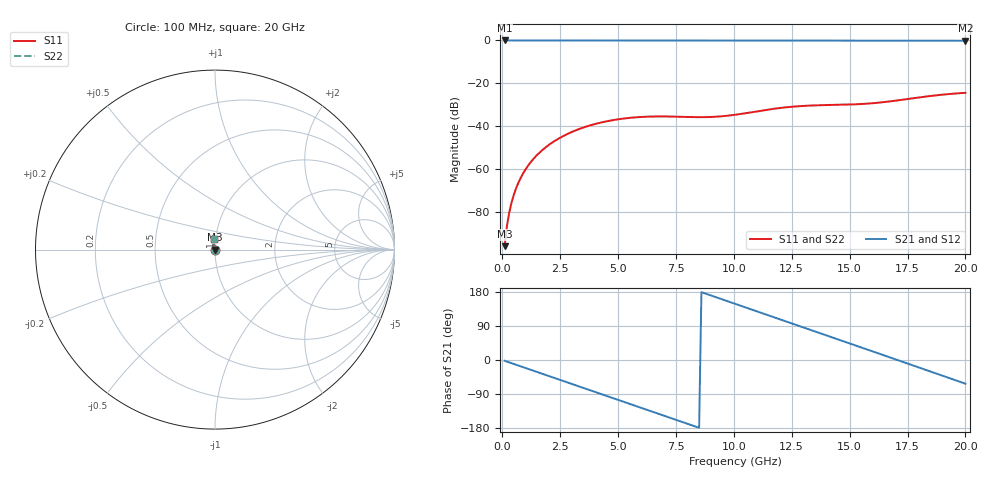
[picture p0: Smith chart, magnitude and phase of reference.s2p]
! circuitRF F0 spike reference -- case B, openEMS, lossless dielectric, dw 25 um, stopped at 38.3 ns
! openEMS probes -> S by postproc.py (own time column per probe); port 1 excited only;
! S22 = S11 and S12 = S21 by the 180-degree rotational symmetry (not a second run)
# GHz S RI R 50
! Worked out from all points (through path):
!   200 points, 100 MHz to 20 GHz, reference 50 ohm
!   highest |S21| = 0.00 dB at 100 MHz (marker M1); lowest = -0.1 dB at 20 GHz (marker M2)
!   group delay of S21, straight-line fit = 58.7 ps
!   lowest |S11| = -95.9 dB at 100 MHz (marker M3), VSWR 1.00, Z = 50 - j0.00127 ohm
!   |S11| at or under -10 dB: start of sweep to end of sweep
!   |S22| runs from -95.9 to -24.4 dB; largest |S21 - S12| = 0
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0.1  -9.8e-06 -1.27e-05  0.9993 -0.0367  0.9993 -0.0367  -9.8e-06 -1.27e-05
0.3  -9.2e-05 -3.18e-05  0.9939 -0.1098  0.9939 -0.1098  -9.2e-05 -3.18e-05
0.5  -0.000253 -2.93e-05  0.9832 -0.1824  0.9832 -0.1824  -0.000253 -2.93e-05
0.7  -0.000489 6.37e-06  0.9672 -0.254  0.9672 -0.254  -0.000489 6.37e-06
1  -0.000968 0.00015  0.9334 -0.3587  0.9334 -0.3587  -0.000968 0.00015
1.4  -0.00178 0.00056  0.8709 -0.4913  0.8709 -0.4913  -0.00178 0.00056
2.3  -0.00389 0.00261  0.6645 -0.7471  0.6645 -0.7471  -0.00389 0.00261
3.5  -0.00559 0.00749  0.2826 -0.959  0.2826 -0.959  -0.00559 0.00749
4.3  -0.00522 0.0112  -0.00713 -0.9995  -0.00713 -0.9995  -0.00522 0.0112
5.1  -0.00371 0.0143  -0.2962 -0.9544  -0.2962 -0.9544  -0.00371 0.0143
6.8  0.000394 0.0169  -0.798 -0.6004  -0.798 -0.6004  0.000394 0.0169
7.7  0.0011 0.0166  -0.9494 -0.3083  -0.9494 -0.3083  0.0011 0.0166
8.5  0.000355 0.0163  -0.9975 -0.0195  -0.9975 -0.0195  0.000355 0.0163
10.1  -0.00353 0.0183  -0.8387 0.5376  -0.8387 0.5376  -0.00353 0.0183
11.8  -0.00618 0.0251  -0.363 0.925  -0.363 0.925  -0.00618 0.0251
12.6  -0.00551 0.0282  -0.0785 0.9893  -0.0785 0.9893  -0.00551 0.0282
13.4  -0.0045 0.0302  0.2123 0.9684  0.2123 0.9684  -0.0045 0.0302
14.3  -0.00412 0.0312  0.5159 0.8453  0.5159 0.8453  -0.00412 0.0312
15.2  -0.0053 0.032  0.7629 0.63  0.7629 0.63  -0.0053 0.032
16.7  -0.0101 0.0364  0.9788 0.1331  0.9788 0.1331  -0.0101 0.0364
18.3  -0.013 0.0475  0.8843 -0.4362  0.8843 -0.4362  -0.013 0.0475
20  -0.00669 0.0597  0.455 -0.8728  0.455 -0.8728  -0.00669 0.0597
